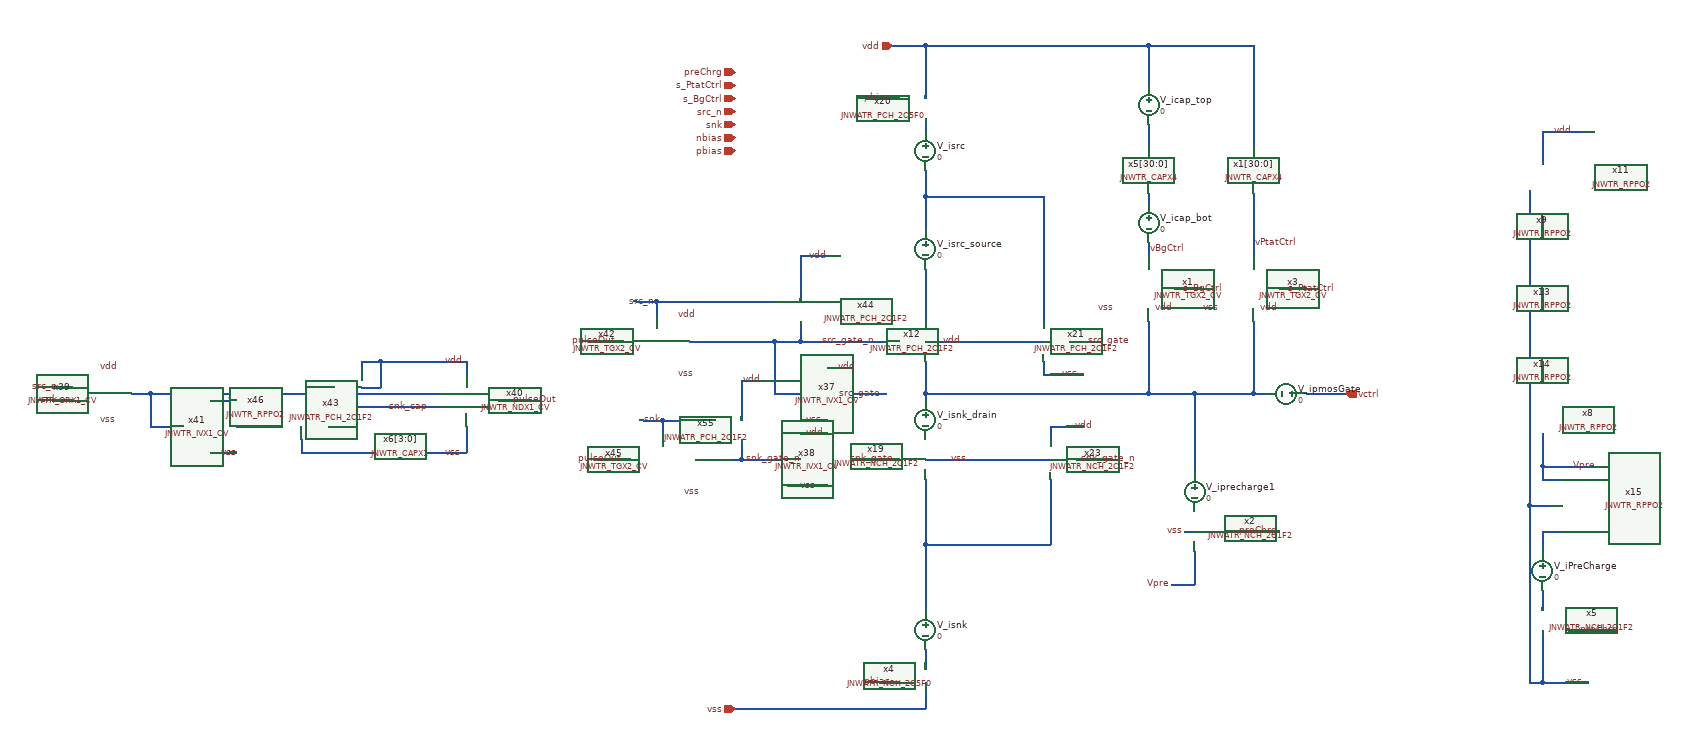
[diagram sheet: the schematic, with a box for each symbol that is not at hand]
v {xschem version=3.4.6 file_version=1.2}
G {}
K {}
V {}
S {}
E {}
N 260 -830 600 -830 {
lab=vdd}
N 260 -830 260 -750 {
lab=vdd}
N 260 140 260 180 {
lab=vss}
N 170 -750 220 -750 {
lab=pbias}
N 190 140 220 140 {
lab=nbias}
N 1200 -190 1280 -190 {
lab=Vpre}
N 260 -350 260 -300 {
lab=#net1}
N 440 -350 440 -330 {
lab=vss}
N 440 -330 500 -330 {
lab=vss}
N 480 -380 505 -380 {
lab=src_gate}
N 450 -250 450 -230 {
lab=vdd}
N 450 -250 500 -250 {
lab=vdd}
N 260 90 260 120 {
lab=#net2}
N 260 -720 260 -700 {
lab=#net3}
N 1200 60 1200 140 {
lab=vss}
N 1240 60 1310 60 {
lab=preChrg}
N 1200 0 1200 30 {
lab=#net4}
N 1200 -90 1200 -60 {
lab=#net5}
N 1200 140 1270 140 {
lab=vss}
N 1180 140 1200 140 {
lab=vss}
N 1200 -570 1200 -540 {
lab=#net6}
N 1200 -700 1200 -650 {
lab=vdd}
N 1200 -700 1260 -700 {
lab=vdd}
N 1200 -460 1200 -430 {
lab=#net7}
N 260 -300 260 -290 {
lab=#net1}
N 260 -600 440 -600 {
lab=#net8}
N 260 -640 260 -600 {
lab=#net8}
N -30 180 260 180 {
lab=vss}
N 260 -380 440 -380 {
lab=vdd}
N 260 -70 260 30 {
lab=#net9}
N 450 -170 450 -70 {
lab=#net9}
N 260 -70 450 -70 {
lab=#net9}
N 260 -170 260 -70 {
lab=#net9}
N 440 -600 440 -410 {
lab=#net8}
N 600 -605 600 -590 {
lab=#net10}
N 600 -300 670 -300 {
lab=#net1}
N 600 -710 600 -675 {
lab=#net11}
N 600 -830 600 -770 {
lab=vdd}
N 260 -600 260 -550 {
lab=#net8}
N 260 -490 260 -410 {
lab=#net12}
N 710 -90 800 -90 {
lab=preChrg}
N 655 -90 670 -90 {
lab=vss}
N 670 -60 670 -10 {
lab=Vpre}
N 635 -10 670 -10 {
lab=Vpre}
N 670 -300 670 -180 {
lab=#net1}
N 1200 -190 1200 -170 {lab=Vpre}
N 1180 -130 1180 140 {
lab=vss}
N 1200 -170 1230 -170 {lab=Vpre}
N 1200 -90 1230 -90 {lab=#net5}
N 1180 -130 1210 -130 {lab=vss}
N 1200 -240 1200 -190 {lab=Vpre}
N 1200 -350 1200 -320 {lab=#net13}
N 1180 -610 1180 -130 {
lab=vss}
N -680 -300 -480 -300 {
lab=#net14}
N -440 -350 -440 -330 {
lab=vdd}
N -440 -250 -440 -210 {
lab=vss}
N -920 -300 -920 -250 {
lab=#net14}
N -630 -280 -630 -250 {
lab=snk_cap}
N -630 -280 -480 -280 {
lab=snk_cap}
N -690 -230 -690 -210 {
lab=vss}
N -650 -250 -630 -250 {
lab=snk_cap}
N 70 -380 220 -380 {
lab=src_gate_n}
N 105 -260 110 -260 {
lab=vss}
N 110 -340 125 -340 {
lab=vdd}
N 30 -380 30 -300 {
lab=src_gate_n}
N 30 -300 70 -300 {
lab=src_gate_n}
N 150 -300 200 -300 {
lab=src_gate}
N 70 -240 110 -240 {
lab=vdd}
N -790 -250 -730 -250 {
lab=#net15}
N -920 -250 -870 -250 {
lab=#net14}
N -830 -210 -790 -210 {
lab=vss}
N -830 -290 -790 -290 {
lab=vdd}
N -690 -210 -440 -210 {
lab=vss}
N 50 -160 110 -160 {
lab=vss}
N -950 -300 -920 -300 {
lab=#net14}
N -600 -350 -600 -340 {
lab=vdd}
N -570 -350 -440 -350 {
lab=vdd}
N -680 -310 -640 -310 {
lab=#net14}
N -680 -310 -680 -300 {
lab=#net14}
N -920 -300 -680 -300 {
lab=#net14}
N -600 -310 -570 -310 {
lab=vdd}
N -570 -350 -570 -310 {
lab=vdd}
N -600 -350 -570 -350 {
lab=vdd}
N -1070 -290 -1040 -290 {lab=snk}
N -1070 -310 -1040 -310 {lab=src_n}
N -390 -290 -340 -290 {lab=pulseOut}
N -150 -440 -150 -420 {lab=src_n}
N -180 -440 -150 -440 {lab=src_n}
N -100 -380 30 -380 {lab=src_gate_n}
N -250 -380 -200 -380 {lab=pulseOut}
N 70 -410 70 -380 {lab=src_gate_n}
N 30 -380 70 -380 {
lab=src_gate_n}
N 70 -510 70 -440 {lab=vdd}
N 70 -510 110 -510 {lab=vdd}
N -150 -440 30 -440 {lab=src_n}
N -140 -260 -140 -240 {lab=snk}
N -170 -260 -140 -260 {lab=snk}
N -240 -200 -190 -200 {lab=pulseOut}
N -140 -260 -60 -260 {lab=snk}
N -20 -320 -20 -260 {lab=vdd}
N -20 -320 0 -320 {lab=vdd}
N 600 -830 760 -830 {lab=vdd}
N 600 -530 600 -510 {lab=vBgCtrl}
N 600 -410 600 -300 {lab=#net1}
N 260 -300 600 -300 {
lab=#net1}
N 760 -300 780 -300 {
lab=#net1}
N 840 -300 900 -300 {lab=vctrl}
N 640 -460 680 -460 {lab=s_BgCtrl}
N 210 -830 260 -830 {
lab=vdd}
N 260 -200 450 -200 {lab=vss}
N 150 -200 220 -200 {lab=snk_gate}
N -20 -200 70 -200 {lab=snk_gate_n}
N -20 -230 -20 -200 {lab=snk_gate_n}
N -90 -200 -20 -200 {lab=snk_gate_n}
N 490 -200 540 -200 {lab=snk_gate_n}
N 760 -830 760 -675 {lab=vdd}
N 760 -605 760 -510 {lab=vPtatCtrl}
N 760 -410 760 -300 {lab=#net1}
N 800 -460 840 -460 {lab=s_PtatCtrl}
N 670 -300 760 -300 {
lab=#net1}
C {devices/ipin.sym} 210 -830 0 0 {name=p1 lab=vdd}
C {devices/opin.sym} 900 -300 0 0 {name=p2 lab=vctrl}
C {devices/ipin.sym} -30 180 0 0 {name=p3 lab=vss
}
C {devices/ipin.sym} -30 -690 0 0 {name=p6 lab=nbias
}
C {devices/ipin.sym} -30 -670 0 0 {name=p7 lab=pbias
}
C {JNW_TR_SKY130A/JNWTR_CAPX4.sym} 600 -615 0 0 {name=x5[30:0]}
C {devices/ipin.sym} -30 -790 0 0 {name=p10 lab=preChrg
}
C {devices/lab_wire.sym} 1215 -700 0 1 {name=p19 sig_type=std_logic lab=vdd}
C {JNW_ATR_SKY130A/JNWATR_NCH_2C5F0.sym} 220 140 0 0 {name=x4 }
C {devices/lab_wire.sym} 285 -380 0 1 {name=p22 sig_type=std_logic lab=vdd}
C {devices/lab_wire.sym} 1235 140 0 1 {name=p17 sig_type=std_logic lab=vss}
C {devices/lab_wire.sym} 1245 -190 0 1 {name=p13 sig_type=std_logic lab=Vpre}
C {devices/lab_wire.sym} 635 -10 0 0 {name=p20 sig_type=std_logic lab=Vpre}
C {JNW_ATR_SKY130A/JNWATR_PCH_2C1F2.sym} 220 -380 0 0 {name=x12 }
C {JNW_ATR_SKY130A/JNWATR_NCH_2C1F2.sym} 220 -200 0 0 {name=x19 }
C {JNW_ATR_SKY130A/JNWATR_PCH_2C1F2.sym} 480 -380 0 1 {name=x21 }
C {devices/lab_wire.sym} 495 -330 0 0 {name=p26 sig_type=std_logic lab=vss}
C {devices/lab_wire.sym} 505 -380 0 1 {name=p28 sig_type=std_logic lab=src_gate}
C {JNW_ATR_SKY130A/JNWATR_NCH_2C1F2.sym} 490 -200 0 1 {name=x23 }
C {devices/lab_wire.sym} 325 -200 0 0 {name=p31 sig_type=std_logic lab=vss}
C {devices/lab_wire.sym} 495 -200 0 1 {name=p33 sig_type=std_logic lab=snk_gate_n}
C {devices/vsource.sym} 260 -670 0 0 {name=V_isrc value=0 savecurrent=true}
C {devices/vsource.sym} 260 60 0 0 {name=V_isnk value=0 savecurrent=true}
C {JNW_ATR_SKY130A/JNWATR_PCH_2C5F0.sym} 220 -750 0 0 {name=x20 }
C {devices/vsource.sym} 1200 -30 0 0 {name=V_iPreCharge value=0 savecurrent=true}
C {JNW_ATR_SKY130A/JNWATR_NCH_2C1F2.sym} 1240 60 0 1 {name=x5 }
C {devices/lab_wire.sym} 1255 60 0 1 {name=p39 sig_type=std_logic lab=preChrg}
C {JNW_TR_SKY130A/JNWTR_RPPO2.sym} 1200 -170 1 0 {name=x8 }
C {JNW_TR_SKY130A/JNWTR_RPPO2.sym} 1200 -540 1 0 {name=x9 }
C {JNW_TR_SKY130A/JNWTR_RPPO2.sym} 1200 -650 1 0 {name=x11 }
C {JNW_TR_SKY130A/JNWTR_RPPO2.sym} 1200 -430 1 0 {name=x13 }
C {devices/vsource.sym} 260 -260 0 0 {name=V_isnk_drain value=0 savecurrent=true}
C {devices/vsource.sym} 260 -520 0 0 {name=V_isrc_source value=0 savecurrent=true}
C {devices/lab_wire.sym} 485 -250 0 1 {name=p32 sig_type=std_logic lab=vdd}
C {devices/vsource.sym} 600 -560 0 0 {name=V_icap_bot value=0 savecurrent=true}
C {devices/vsource.sym} 670 -150 0 0 {name=V_iprecharge1 value=0 savecurrent=true}
C {devices/vsource.sym} 810 -300 1 0 {name=V_ipmosGate value=0 savecurrent=true}
C {devices/vsource.sym} 600 -740 0 0 {name=V_icap_top value=0 savecurrent=true}
C {JNW_ATR_SKY130A/JNWATR_NCH_2C1F2.sym} 710 -90 0 1 {name=x2 }
C {devices/lab_wire.sym} 655 -90 0 0 {name=p8 sig_type=std_logic lab=vss}
C {JNW_TR_SKY130A/JNWTR_RPPO2.sym} 1200 -320 1 0 {name=x14 }
C {JNW_TR_SKY130A/JNWTR_RPPO2.sym} 1230 -170 1 0 {name=x15 }
C {devices/ipin.sym} -30 -710 0 0 {name=p68 lab=snk
}
C {devices/ipin.sym} -30 -730 0 0 {name=p69 lab=src_n}
C {devices/lab_wire.sym} -475 -350 0 1 {name=p70 sig_type=std_logic lab=vdd}
C {devices/lab_wire.sym} -475 -210 0 1 {name=p71 sig_type=std_logic lab=vss}
C {devices/lab_wire.sym} 185 -380 0 0 {name=p72 sig_type=std_logic lab=src_gate_n}
C {devices/lab_wire.sym} 215 -200 0 0 {name=p73 sig_type=std_logic lab=snk_gate}
C {JNW_TR_SKY130A/JNWTR_CAPX1.sym} -540 -220 0 0 {name=x6[3:0]}
C {devices/lab_wire.sym} -495 -280 0 0 {name=p77 sig_type=std_logic lab=snk_cap}
C {JNW_TR_SKY130A/JNWTR_IVX1_CV.sym} 70 -300 0 0 {name=x37 }
C {devices/lab_wire.sym} 125 -340 0 1 {name=p78 sig_type=std_logic lab=vdd}
C {devices/lab_wire.sym} 105 -260 0 0 {name=p79 sig_type=std_logic lab=vss}
C {devices/lab_wire.sym} 195 -300 0 0 {name=p80 sig_type=std_logic lab=src_gate}
C {JNW_TR_SKY130A/JNWTR_IVX1_CV.sym} 70 -200 0 0 {name=x38 }
C {devices/lab_wire.sym} -15 -200 0 1 {name=p81 sig_type=std_logic lab=snk_gate_n}
C {JNW_TR_SKY130A/JNWTR_NDX1_CV.sym} -480 -280 0 0 {name=x40 }
C {devices/lab_wire.sym} 95 -160 0 0 {name=p82 sig_type=std_logic lab=vss}
C {devices/lab_wire.sym} 75 -240 0 1 {name=p83 sig_type=std_logic lab=vdd}
C {JNW_TR_SKY130A/JNWTR_IVX1_CV.sym} -870 -250 0 0 {name=x41 }
C {devices/lab_wire.sym} -815 -210 0 1 {name=p84 sig_type=std_logic lab=vss}
C {devices/lab_wire.sym} -805 -290 0 1 {name=p86 sig_type=std_logic lab=vdd}
C {JNW_ATR_SKY130A/JNWATR_PCH_2C1F2.sym} -640 -310 0 0 {name=x43 }
C {JNW_TR_SKY130A/JNWTR_RPPO2.sym} -730 -250 0 0 {name=x46 }
C {JNW_TR_SKY130A/JNWTR_ORX1_CV.sym} -1040 -290 0 0 {name=x39 }
C {devices/lab_wire.sym} -1000 -340 0 1 {name=p74 sig_type=std_logic lab=vdd

}
C {devices/lab_wire.sym} -1000 -260 0 1 {name=p75 sig_type=std_logic lab=vss

}
C {devices/lab_wire.sym} -370 -290 0 1 {name=p76 sig_type=std_logic lab=pulseOut

}
C {JNW_TR_SKY130A/JNWTR_TGX2_CV.sym} -210 -380 0 0 {name=x42 }
C {devices/lab_wire.sym} -120 -420 0 1 {name=p85 sig_type=std_logic lab=vdd

}
C {devices/lab_wire.sym} -120 -330 0 1 {name=p87 sig_type=std_logic lab=vss

}
C {devices/lab_wire.sym} -150 -440 0 0 {name=p91 sig_type=std_logic lab=src_n

}
C {devices/lab_wire.sym} -210 -380 0 0 {name=p92 sig_type=std_logic lab=pulseOut

}
C {devices/lab_wire.sym} 80 -510 0 1 {name=p93 sig_type=std_logic lab=vdd

}
C {JNW_TR_SKY130A/JNWTR_TGX2_CV.sym} -200 -200 0 0 {name=x45 }
C {devices/lab_wire.sym} -110 -240 0 1 {name=p94 sig_type=std_logic lab=vdd

}
C {devices/lab_wire.sym} -110 -150 0 1 {name=p95 sig_type=std_logic lab=vss

}
C {devices/lab_wire.sym} -140 -260 0 0 {name=p96 sig_type=std_logic lab=snk

}
C {devices/lab_wire.sym} -200 -200 0 0 {name=p97 sig_type=std_logic lab=pulseOut

}
C {JNW_ATR_SKY130A/JNWATR_PCH_2C1F2.sym} 30 -440 0 0 {name=x44 }
C {JNW_ATR_SKY130A/JNWATR_PCH_2C1F2.sym} -60 -260 0 0 {name=x55 }
C {devices/lab_wire.sym} -20 -320 0 1 {name=p98 sig_type=std_logic lab=vdd

}
C {JNW_TR_SKY130A/JNWTR_TGX2_CV.sym} 600 -520 1 0 {name=x1 }
C {devices/lab_wire.sym} 640 -430 1 1 {name=p4 sig_type=std_logic lab=vdd

}
C {devices/lab_wire.sym} 550 -430 1 1 {name=p5 sig_type=std_logic lab=vss

}
C {devices/lab_wire.sym} 710 -430 1 1 {name=p11 sig_type=std_logic lab=vss

}
C {devices/lab_wire.sym} 650 -460 0 1 {name=p12 sig_type=std_logic lab=s_BgCtrl

}
C {devices/ipin.sym} -30 -770 0 0 {name=p15 lab=s_PtatCtrl
}
C {devices/ipin.sym} -30 -750 0 0 {name=p16 lab=s_BgCtrl
}
C {devices/lab_wire.sym} -1060 -310 0 0 {name=p18 sig_type=std_logic lab=src_n

}
C {devices/lab_wire.sym} -1060 -290 0 0 {name=p21 sig_type=std_logic lab=snk

}
C {devices/lab_wire.sym} 735 -90 0 1 {name=p23 sig_type=std_logic lab=preChrg}
C {devices/lab_wire.sym} 210 -750 0 0 {name=p24 sig_type=std_logic lab=pbias

}
C {devices/lab_wire.sym} 210 140 0 0 {name=p25 sig_type=std_logic lab=nbias

}
C {JNW_TR_SKY130A/JNWTR_CAPX4.sym} 760 -615 0 0 {name=x1[30:0]}
C {JNW_TR_SKY130A/JNWTR_TGX2_CV.sym} 760 -520 1 0 {name=x3 }
C {devices/lab_wire.sym} 800 -430 1 1 {name=p9 sig_type=std_logic lab=vdd

}
C {devices/lab_wire.sym} 810 -460 0 1 {name=p14 sig_type=std_logic lab=s_PtatCtrl

}
C {devices/lab_wire.sym} 760 -530 0 1 {name=p27 sig_type=std_logic lab=vPtatCtrl

}
C {devices/lab_wire.sym} 600 -520 0 1 {name=p29 sig_type=std_logic lab=vBgCtrl

}
